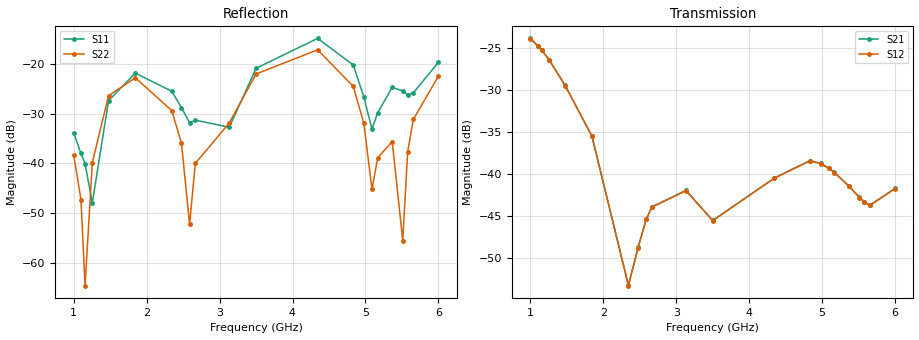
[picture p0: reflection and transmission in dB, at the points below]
!Agilent Technologies,E8364B,MY43040528,A.07.50.67
!Agilent E8364B: A.07.50.67
!Date: Sunday, March 01, 2026 16:44:42
!Correction: S11(Full 2 Port(1,2))
!S21(Full 2 Port(1,2))
!S12(Full 2 Port(1,2))
!S22(Full 2 Port(1,2))
!S2P File: Measurements: S11, S21, S12, S22:
# Hz S  dB  R 50
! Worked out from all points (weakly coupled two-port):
!   451 points, 1 GHz to 6 GHz, reference 50 ohm
!   highest |S21| = -23.84 dB at 1 GHz (marker M1); lowest = -53.2 dB at 2.344 GHz (marker M2)
!   lowest |S11| = -48.0 dB at 1.256 GHz (marker M3), VSWR 1.01, Z = 49.9 + j0.378 ohm
!   |S11| at or under -10 dB: start of sweep to end of sweep
!   |S22| runs from -68.5 to -17.0 dB; largest |S21 - S12| = 0.0003
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1e9  -33.87 31.9  -23.84 153.2  -23.88 153.3  -38.34 -32.1
1.1e9  -38.02 41.5  -24.70 95.9  -24.73 96.0  -47.28 -45.7
1.155556e9  -40.05 47.6  -25.24 64.3  -25.27 64.3  -64.61 -34.3
1.255556e9  -47.97 108.4  -26.36 7.5  -26.39 7.5  -39.87 153.3
1.477778e9  -27.41 145.0  -29.45 -115.7  -29.48 -115.6  -26.42 93.4
1.844444e9  -21.86 75.7  -35.48 48.4  -35.51 48.5  -22.80 -1.3
2.344444e9  -25.50 13.7  -53.24 -149.6  -53.29 -149.7  -29.39 -111.0
2.477778e9  -28.81 5.1  -48.69 -167.2  -48.76 -167.1  -35.94 -147.3
2.588889e9  -31.85 19.9  -45.36 143.8  -45.40 143.9  -52.29 101.7
2.666667e9  -31.33 35.9  -43.90 105.0  -43.94 105.0  -40.03 1.2
3.133333e9  -32.74 52.5  -41.94 -141.4  -41.99 -141.3  -31.87 -29.6
3.5e9  -20.89 47.2  -45.52 37.9  -45.55 38.0  -22.03 -105.5
4.344444e9  -14.87 -44.6  -40.47 24.2  -40.50 24.2  -17.17 103.4
4.833333e9  -20.24 -120.3  -38.39 109.4  -38.43 109.5  -24.54 -14.9
4.977778e9  -26.67 -133.4  -38.72 24.4  -38.76 24.5  -31.99 -61.7
5.088889e9  -33.09 -94.8  -39.26 -42.0  -39.31 -41.9  -45.26 -158.1
5.166667e9  -29.85 -60.4  -39.77 -89.0  -39.82 -89.0  -38.91 99.3
5.366667e9  -24.72 -70.6  -41.42 146.0  -41.46 146.0  -35.63 26.0
5.511111e9  -25.44 -78.3  -42.75 49.6  -42.80 49.6  -55.56 71.1
5.577778e9  -26.18 -74.2  -43.29 2.8  -43.33 2.9  -37.77 119.7
5.655556e9  -25.84 -65.6  -43.69 -53.4  -43.74 -53.4  -31.17 102.1
6e9  -19.68 -73.1  -41.70 61.6  -41.73 61.6  -22.47 4.2
